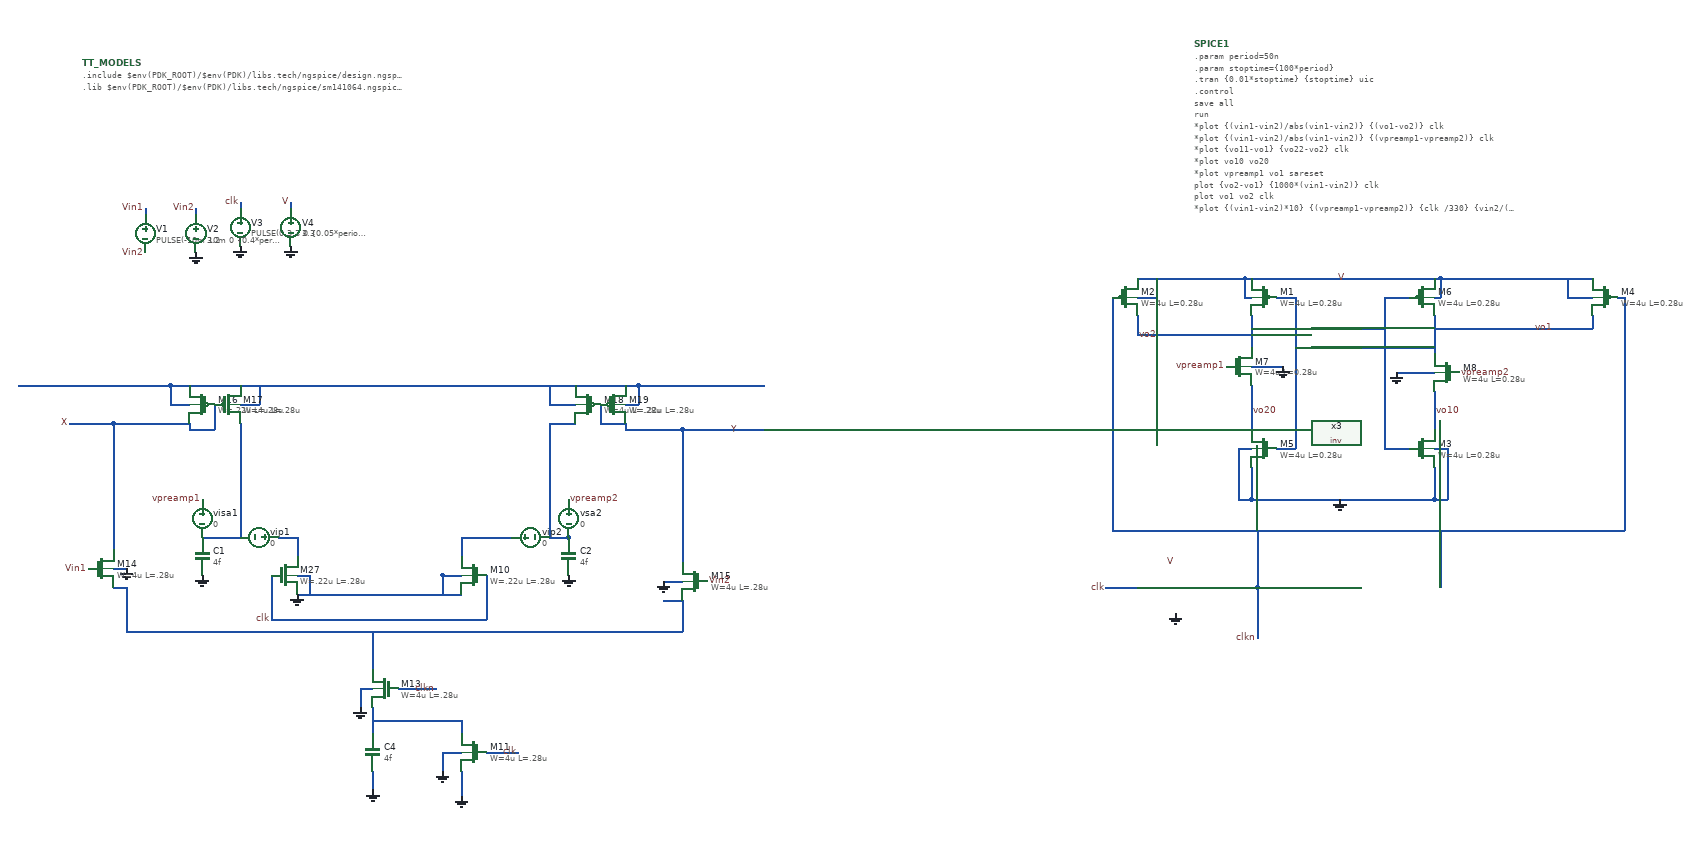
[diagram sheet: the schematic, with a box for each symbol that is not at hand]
v {xschem version=3.4.6RC file_version=1.2
}
G {}
K {}
V {}
S {}
E {}
N 270 -480 270 -470 {
lab=V}
N 190 -480 190 -470 {
lab=clk}
N 1790 -60 1790 -10 {
lab=GND}
N 1850 40 2350 40 {
lab=clkn}
N 2080 -60 2080 -10 {
lab=GND}
N 1770 -90 1790 -90 {
lab=GND}
N 1770 -90 1770 -10 {
lab=GND}
N 2080 -90 2100 -90 {
lab=GND}
N 2100 -90 2100 -10 {
lab=GND}
N 2080 -130 2080 -120 {
lab=vo10}
N 2080 -300 2080 -240 {
lab=vo1}
N 2020 -360 2090 -360 {
lab=V}
N 1790 -130 1790 -120 {
lab=vo20}
N 1790 -300 1790 -250 {
lab=vo2}
N 1780 -330 1790 -330 {
lab=V}
N 1780 -360 1780 -330 {
lab=V}
N 2080 -330 2090 -330 {
lab=V}
N 2090 -360 2090 -330 {
lab=V}
N 1830 -330 1860 -330 {
lab=vo1}
N 1830 -90 1860 -90 {
lab=vo1}
N 1860 -170 1860 -90 {
lab=vo1}
N 1790 -220 1840 -220 {
lab=GND}
N 2000 -130 2000 -90 {
lab=vo2}
N 2000 -90 2040 -90 {
lab=vo2}
N 2020 -210 2080 -210 {
lab=GND}
N 2000 -330 2040 -330 {
lab=vo2}
N 1770 -10 1790 -10 {
lab=GND}
N 1920 -10 2080 -10 {
lab=GND}
N 2080 -10 2100 -10 {
lab=GND}
N 1780 -360 1840 -360 {
lab=V}
N 1940 -360 2020 -360 {
lab=V}
N 1860 -330 1860 -170 {
lab=vo1}
N 2080 -180 2080 -170 {
lab=vo10}
N 1790 -190 1790 -130 {
lab=vo20}
N 2000 -330 2000 -130 {
lab=vo2}
N 2080 -170 2080 -130 {
lab=vo10}
N 1840 -360 1940 -360 {
lab=V}
N 1790 -10 1920 -10 {
lab=GND}
N 1560 130 1610 130 {
lab=clk}
N 2090 40 2090 130 {lab=clkn}
N 120 -470 120 -460 {
lab=Vin2}
N 40 -470 40 -460 {
lab=Vin1}
N 710 50 710 60 {lab=#net1}
N 2090 -360 2330 -360 {lab=V}
N 1610 -360 1780 -360 {lab=V}
N 1610 -330 1640 -330 {lab=V}
N 1640 -360 1640 -330 {lab=V}
N 2290 -330 2330 -330 {lab=V}
N 2290 -360 2290 -330 {lab=V}
N 1610 -300 1610 -270 {lab=vo2}
N 1610 -270 1790 -270 {lab=vo2}
N 2080 -280 2330 -280 {lab=vo1}
N 2330 -300 2330 -280 {lab=vo1}
N 2350 40 2380 40 {lab=clkn}
N 2380 -330 2380 40 {lab=clkn}
N 2370 -330 2380 -330 {lab=clkn}
N 1570 -330 1570 -10 {lab=clkn}
N 1570 -10 1570 40 {lab=clkn}
N 1570 40 1850 40 {lab=clkn}
N 300 110 300 140 {lab=GND}
N 280 140 540 140 {lab=GND}
N 510 110 510 140 {lab=GND}
N 240 110 240 180 {lab=clk}
N 240 180 580 180 {lab=clk}
N 580 110 580 180 {lab=clk}
N 710 50 710 60 {lab=#net1}
N 130 50 130 60 {lab=#net2}
N 130 50 190 50 {lab=#net2}
N 250 50 280 50 {lab=#net3}
N 540 50 620 50 {lab=#net4}
N 680 50 710 50 {lab=#net1}
N 1790 -280 2000 -280 {lab=vo2}
N 1860 -250 2080 -250 {lab=vo1}
N 540 50 540 80 {lab=#net4}
N 280 50 280 80 {lab=#net3}
N 510 110 540 110 {lab=GND}
N 280 110 300 110 {lab=GND}
N 510 110 540 110 {lab=GND}
N 110 -190 800 -190 {lab=#net5}
N 80 -160 110 -160 {lab=#net5}
N 80 -190 80 -160 {lab=#net5}
N 80 -190 110 -190 {lab=#net5}
N 190 -160 220 -160 {lab=#net5}
N 220 -190 220 -160 {lab=#net5}
N 680 -160 720 -160 {lab=#net5}
N 680 -190 680 -160 {lab=#net5}
N 800 -160 820 -160 {lab=#net5}
N 820 -190 820 -160 {lab=#net5}
N 800 -190 820 -190 {lab=#net5}
N 860 120 890 120 {lab=GND}
N 860 150 890 150 {lab=#net6}
N -10 100 10 100 {lab=GND}
N -10 130 10 130 {lab=#net6}
N 150 -160 150 -120 {lab=X}
N 110 -120 150 -120 {lab=X}
N 110 -130 110 -120 {lab=X}
N 0 -130 110 -130 {lab=X}
N 190 -130 190 50 {lab=#net2}
N 680 -130 720 -130 {lab=#net1}
N 680 -130 680 50 {lab=#net1}
N 380 290 400 290 {lab=GND}
N 380 290 380 320 {lab=GND}
N 10 130 10 200 {lab=#net6}
N 10 200 890 200 {lab=#net6}
N 890 150 890 200 {lab=#net6}
N 400 200 400 260 {lab=#net6}
N 760 -130 800 -130 {lab=Y}
N 760 -160 760 -130 {lab=Y}
N 1770 130 1800 130 {lab=clkn}
N 1800 40 1800 130 {lab=clkn}
N 900 -120 1020 -120 {lab=Y}
N -80 -190 80 -190 {lab=#net5}
N 820 -190 1020 -190 {lab=#net5}
N 890 20 890 90 {lab=Y}
N -160 -190 -80 -190 {lab=#net5}
N 510 390 540 390 {lab=GND}
N 510 390 510 420 {lab=GND}
N 400 420 400 450 {lab=GND}
N 400 320 400 360 {lab=#net7}
N 400 340 540 340 {lab=#net7}
N 540 340 540 360 {lab=#net7}
N 540 420 540 460 {lab=GND}
N 890 -120 890 20 {lab=Y}
N 890 -120 900 -120 {lab=Y}
N -10 -130 -10 70 {lab=X}
N -10 -130 -0 -130 {lab=X}
N -80 -130 -10 -130 {lab=X}
N 800 -130 800 -120 {lab=Y}
N 800 -120 890 -120 {lab=Y}
N 580 390 630 390 {lab=clk}
N 1800 130 1800 210 {lab=clkn}
N 440 290 500 290 {lab=clkn}
C {devices/vsource.sym} 190 -440 0 0 {name=V3 value="PULSE(0 3.3 0 \{0.05*period\} \{0.05*period\} \{0.5*period\} \{1*period\})"}
C {devices/gnd.sym} 190 -410 0 0 {name=l4 lab=GND}
C {devices/lab_wire.sym} 190 -480 0 0 {name=p3 sig_type=std_logic lab=clk
}
C {devices/vsource.sym} 270 -440 0 0 {name=V4 value=3.3}
C {devices/gnd.sym} 270 -410 0 0 {name=l5 lab=GND}
C {devices/lab_wire.sym} 270 -480 0 0 {name=p7 sig_type=std_logic lab=V
}
C {devices/code_shown.sym} 1700 -730 0 0 {name=SPICE1 only_toplevel=false value="

.param period=50n
.param stoptime=\{100*period\}
.tran \{0.01*stoptime\} \{stoptime\} uic 
.control
save all
run
*plot \{(vin1-vin2)/abs(vin1-vin2)\} \{(vo1-vo2)\} clk
*plot \{(vin1-vin2)/abs(vin1-vin2)\} \{(vpreamp1-vpreamp2)\} clk
*plot \{vo11-vo1\} \{vo22-vo2\} clk
*plot vo10 vo20
*plot vpreamp1 vo1 sareset
plot \{vo2-vo1\} \{1000*(vin1-vin2)\} clk
plot vo1 vo2 clk
*plot \{(vin1-vin2)*10\} \{(vpreamp1-vpreamp2)\} \{clk /330\} \{vin2/(100)\}
plot \{(vin1-vin2)*1000\} vpreamp1 vpreamp2 \{clk\} \{vin2\}
plot \{(vpreamp1-vpreamp2)\} \{(vin1-vin2)\} \{clk/330\}
plot X Y clk
plot \{(X-Y)\} \{clk/3000\}
plot vpreamp1
*plot clk sareset
*plot i(vip1) i(vip2) i(visa1) i(vsa2) clk/3300
.endc"}
C {devices/code.sym} -60 -700 0 0 {name=TT_MODELS 
only_toplevel=true 
format="tcleval(  @value  )"
value="
.include $env(PDK_ROOT)/$env(PDK)/libs.tech/ngspice/design.ngspice
.lib $env(PDK_ROOT)/$env(PDK)/libs.tech/ngspice/sm141064.ngspice typical
"
spice_ignore=false}
C {symbols/pfet_03v3.sym} 1810 -330 0 1 {name=M1
L=0.28u
W=4u
nf=1
m=1
ad="'int((nf+1)/2) * W/nf * 0.18u'"
pd="'2*int((nf+1)/2) * (W/nf + 0.18u)'"
as="'int((nf+2)/2) * W/nf * 0.18u'"
ps="'2*int((nf+2)/2) * (W/nf + 0.18u)'"
nrd="'0.18u / W'" nrs="'0.18u / W'"
sa=0 sb=0 sd=0
model=pfet_03v3
spiceprefix=X
}
C {symbols/pfet_03v3.sym} 1590 -330 0 0 {name=M2
L=0.28u
W=4u
nf=1
m=1
ad="'int((nf+1)/2) * W/nf * 0.18u'"
pd="'2*int((nf+1)/2) * (W/nf + 0.18u)'"
as="'int((nf+2)/2) * W/nf * 0.18u'"
ps="'2*int((nf+2)/2) * (W/nf + 0.18u)'"
nrd="'0.18u / W'" nrs="'0.18u / W'"
sa=0 sb=0 sd=0
model=pfet_03v3
spiceprefix=X
}
C {symbols/nfet_03v3.sym} 2060 -90 0 0 {name=M3
L=0.28u
W=4u
nf=1
m=1
ad="'int((nf+1)/2) * W/nf * 0.18u'"
pd="'2*int((nf+1)/2) * (W/nf + 0.18u)'"
as="'int((nf+2)/2) * W/nf * 0.18u'"
ps="'2*int((nf+2)/2) * (W/nf + 0.18u)'"
nrd="'0.18u / W'" nrs="'0.18u / W'"
sa=0 sb=0 sd=0
model=nfet_03v3
spiceprefix=X
}
C {symbols/pfet_03v3.sym} 2350 -330 0 1 {name=M4
L=0.28u
W=4u
nf=1
m=1
ad="'int((nf+1)/2) * W/nf * 0.18u'"
pd="'2*int((nf+1)/2) * (W/nf + 0.18u)'"
as="'int((nf+2)/2) * W/nf * 0.18u'"
ps="'2*int((nf+2)/2) * (W/nf + 0.18u)'"
nrd="'0.18u / W'" nrs="'0.18u / W'"
sa=0 sb=0 sd=0
model=pfet_03v3
spiceprefix=X
}
C {symbols/nfet_03v3.sym} 1810 -90 0 1 {name=M5
L=0.28u
W=4u
nf=1
m=1
ad="'int((nf+1)/2) * W/nf * 0.18u'"
pd="'2*int((nf+1)/2) * (W/nf + 0.18u)'"
as="'int((nf+2)/2) * W/nf * 0.18u'"
ps="'2*int((nf+2)/2) * (W/nf + 0.18u)'"
nrd="'0.18u / W'" nrs="'0.18u / W'"
sa=0 sb=0 sd=0
model=nfet_03v3
spiceprefix=X
}
C {symbols/pfet_03v3.sym} 2060 -330 0 0 {name=M6
L=0.28u
W=4u
nf=1
m=1
ad="'int((nf+1)/2) * W/nf * 0.18u'"
pd="'2*int((nf+1)/2) * (W/nf + 0.18u)'"
as="'int((nf+2)/2) * W/nf * 0.18u'"
ps="'2*int((nf+2)/2) * (W/nf + 0.18u)'"
nrd="'0.18u / W'" nrs="'0.18u / W'"
sa=0 sb=0 sd=0
model=pfet_03v3
spiceprefix=X
}
C {symbols/nfet_03v3.sym} 1770 -220 0 0 {name=M7
L=0.28u
W=4u
nf=1
m=1
ad="'int((nf+1)/2) * W/nf * 0.18u'"
pd="'2*int((nf+1)/2) * (W/nf + 0.18u)'"
as="'int((nf+2)/2) * W/nf * 0.18u'"
ps="'2*int((nf+2)/2) * (W/nf + 0.18u)'"
nrd="'0.18u / W'" nrs="'0.18u / W'"
sa=0 sb=0 sd=0
model=nfet_03v3
spiceprefix=X
}
C {symbols/nfet_03v3.sym} 2100 -210 0 1 {name=M8
L=0.28u
W=4u
nf=1
m=1
ad="'int((nf+1)/2) * W/nf * 0.18u'"
pd="'2*int((nf+1)/2) * (W/nf + 0.18u)'"
as="'int((nf+2)/2) * W/nf * 0.18u'"
ps="'2*int((nf+2)/2) * (W/nf + 0.18u)'"
nrd="'0.18u / W'" nrs="'0.18u / W'"
sa=0 sb=0 sd=0
model=nfet_03v3
spiceprefix=X
}
C {inv.sym} 1670 130 0 0 {name=x3 cl=0.28u wp=0.44u wn=0.22u wx=4u}
C {symbols/nfet_03v3.sym} 260 110 0 0 {name=M27
L=.28u
W=.22u
nf=1
m=1
ad="'int((nf+1)/2) * W/nf * 0.18u'"
pd="'2*int((nf+1)/2) * (W/nf + 0.18u)'"
as="'int((nf+2)/2) * W/nf * 0.18u'"
ps="'2*int((nf+2)/2) * (W/nf + 0.18u)'"
nrd="'0.18u / W'" nrs="'0.18u / W'"
sa=0 sb=0 sd=0
model=nfet_03v3
spiceprefix=X
}
C {devices/lab_wire.sym} 1940 -360 0 0 {name=p4 lab=V
W=3u}
C {devices/gnd.sym} 1670 170 0 0 {name=l1 lab=GND}
C {devices/gnd.sym} 280 140 0 0 {name=l2 lab=GND}
C {devices/lab_wire.sym} 240 180 0 0 {name=p8 sig_type=std_logic lab=clk
}
C {devices/lab_wire.sym} 1560 130 0 0 {name=p9 sig_type=std_logic lab=clk
}
C {devices/lab_wire.sym} 130 -10 0 0 {name=p10 sig_type=std_logic lab=vpreamp1}
C {devices/lab_wire.sym} 1750 -220 0 0 {name=p12 sig_type=std_logic lab=vpreamp1}
C {devices/lab_wire.sym} 2120 -210 0 1 {name=p14 sig_type=std_logic lab=vpreamp2
}
C {devices/lab_wire.sym} 1670 90 0 0 {name=p16 lab=V
W=3u}
C {devices/lab_wire.sym} 2270 -280 0 0 {name=p15 sig_type=std_logic lab=vo1
}
C {devices/lab_wire.sym} 1610 -270 0 1 {name=p17 sig_type=std_logic lab=vo2}
C {devices/vsource.sym} 40 -430 0 0 {name=V1 value="PULSE(-10m 10m 0 \{0.4*period\} \{0.4*period\} \{4*period\} \{8*period\})"}
C {devices/vsource.sym} 120 -430 0 0 {name=V2 value=3.2}
C {devices/gnd.sym} 120 -400 0 0 {name=l3 lab=GND}
C {devices/lab_wire.sym} 40 -470 0 0 {name=p1 sig_type=std_logic lab=Vin1}
C {devices/lab_wire.sym} 120 -470 0 0 {name=p2 sig_type=std_logic lab=Vin2}
C {devices/lab_wire.sym} 40 -400 0 0 {name=p13 sig_type=std_logic lab=Vin2}
C {devices/vsource.sym} 220 50 1 0 {name=vip1 value=0}
C {devices/vsource.sym} 130 20 0 0 {name=visa1 value=0}
C {devices/vsource.sym} 650 50 3 0 {name=vip2 value=0}
C {devices/vsource.sym} 710 20 0 0 {name=vsa2 value=0}
C {devices/lab_wire.sym} 710 -10 0 1 {name=p23 sig_type=std_logic lab=vpreamp2
}
C {devices/gnd.sym} 1930 -10 0 0 {name=l6 lab=GND}
C {symbols/nfet_03v3.sym} 560 110 0 1 {name=M10
L=.28u
W=.22u
nf=1
m=1
ad="'int((nf+1)/2) * W/nf * 0.18u'"
pd="'2*int((nf+1)/2) * (W/nf + 0.18u)'"
as="'int((nf+2)/2) * W/nf * 0.18u'"
ps="'2*int((nf+2)/2) * (W/nf + 0.18u)'"
nrd="'0.18u / W'" nrs="'0.18u / W'"
sa=0 sb=0 sd=0
model=nfet_03v3
spiceprefix=X
}
C {devices/gnd.sym} 10 100 0 0 {name=l7 lab=GND}
C {devices/gnd.sym} 860 120 0 0 {name=l8 lab=GND}
C {devices/gnd.sym} 2020 -210 0 0 {name=l9 lab=GND}
C {devices/gnd.sym} 1840 -220 0 0 {name=l10 lab=GND}
C {devices/lab_wire.sym} 1790 -150 0 1 {name=p19 sig_type=std_logic lab=vo20}
C {devices/lab_wire.sym} 2080 -150 0 1 {name=p20 sig_type=std_logic lab=vo10}
C {symbols/nfet_03v3.sym} 420 290 0 1 {name=M13
L=.28u
W=4u
nf=1
m=1
ad="'int((nf+1)/2) * W/nf * 0.18u'"
pd="'2*int((nf+1)/2) * (W/nf + 0.18u)'"
as="'int((nf+2)/2) * W/nf * 0.18u'"
ps="'2*int((nf+2)/2) * (W/nf + 0.18u)'"
nrd="'0.18u / W'" nrs="'0.18u / W'"
sa=0 sb=0 sd=0
model=nfet_03v3
spiceprefix=X
}
C {symbols/nfet_03v3.sym} -30 100 0 0 {name=M14
L=.28u
W=4u
nf=1
m=1
ad="'int((nf+1)/2) * W/nf * 0.18u'"
pd="'2*int((nf+1)/2) * (W/nf + 0.18u)'"
as="'int((nf+2)/2) * W/nf * 0.18u'"
ps="'2*int((nf+2)/2) * (W/nf + 0.18u)'"
nrd="'0.18u / W'" nrs="'0.18u / W'"
sa=0 sb=0 sd=0
model=nfet_03v3
spiceprefix=X
}
C {symbols/nfet_03v3.sym} 910 120 0 1 {name=M15
L=.28u
W=4u
nf=1
m=1
ad="'int((nf+1)/2) * W/nf * 0.18u'"
pd="'2*int((nf+1)/2) * (W/nf + 0.18u)'"
as="'int((nf+2)/2) * W/nf * 0.18u'"
ps="'2*int((nf+2)/2) * (W/nf + 0.18u)'"
nrd="'0.18u / W'" nrs="'0.18u / W'"
sa=0 sb=0 sd=0
model=nfet_03v3
spiceprefix=X
}
C {symbols/pfet_03v3.sym} 130 -160 0 1 {name=M16
L=.28u
W=.22u
nf=1
m=1
ad="'int((nf+1)/2) * W/nf * 0.18u'"
pd="'2*int((nf+1)/2) * (W/nf + 0.18u)'"
as="'int((nf+2)/2) * W/nf * 0.18u'"
ps="'2*int((nf+2)/2) * (W/nf + 0.18u)'"
nrd="'0.18u / W'" nrs="'0.18u / W'"
sa=0 sb=0 sd=0
model=pfet_03v3
spiceprefix=X
}
C {symbols/pfet_03v3.sym} 170 -160 0 0 {name=M17
L=.28u
W=4u
nf=1
m=1
ad="'int((nf+1)/2) * W/nf * 0.18u'"
pd="'2*int((nf+1)/2) * (W/nf + 0.18u)'"
as="'int((nf+2)/2) * W/nf * 0.18u'"
ps="'2*int((nf+2)/2) * (W/nf + 0.18u)'"
nrd="'0.18u / W'" nrs="'0.18u / W'"
sa=0 sb=0 sd=0
model=pfet_03v3
spiceprefix=X
}
C {symbols/pfet_03v3.sym} 740 -160 0 1 {name=M18
L=.28u
W=4u
nf=1
m=1
ad="'int((nf+1)/2) * W/nf * 0.18u'"
pd="'2*int((nf+1)/2) * (W/nf + 0.18u)'"
as="'int((nf+2)/2) * W/nf * 0.18u'"
ps="'2*int((nf+2)/2) * (W/nf + 0.18u)'"
nrd="'0.18u / W'" nrs="'0.18u / W'"
sa=0 sb=0 sd=0
model=pfet_03v3
spiceprefix=X
}
C {symbols/pfet_03v3.sym} 780 -160 0 0 {name=M19
L=.28u
W=.22u
nf=1
m=1
ad="'int((nf+1)/2) * W/nf * 0.18u'"
pd="'2*int((nf+1)/2) * (W/nf + 0.18u)'"
as="'int((nf+2)/2) * W/nf * 0.18u'"
ps="'2*int((nf+2)/2) * (W/nf + 0.18u)'"
nrd="'0.18u / W'" nrs="'0.18u / W'"
sa=0 sb=0 sd=0
model=pfet_03v3
spiceprefix=X
}
C {devices/gnd.sym} 400 450 0 0 {name=l11 lab=GND}
C {devices/lab_wire.sym} -50 100 0 0 {name=p22 sig_type=std_logic lab=Vin1}
C {devices/lab_wire.sym} 930 120 0 1 {name=p24 sig_type=std_logic lab=Vin2}
C {devices/lab_wire.sym} 1800 210 0 0 {name=p18 sig_type=std_logic lab=clkn
}
C {devices/lab_wire.sym} -80 -130 0 0 {name=p25 sig_type=std_logic lab=X}
C {devices/lab_wire.sym} 980 -120 0 0 {name=p26 sig_type=std_logic lab=Y}
C {devices/capa.sym} 130 80 0 0 {name=C1
m=1
value=4f
footprint=1206
device="ceramic capacitor"}
C {devices/capa.sym} 710 80 0 0 {name=C2
m=1
value=4f
footprint=1206
device="ceramic capacitor"}
C {devices/gnd.sym} 710 110 0 0 {name=l12 lab=GND}
C {devices/gnd.sym} 130 110 0 0 {name=l13 lab=GND}
C {devices/capa.sym} 400 390 0 0 {name=C4
m=1
value=4f
footprint=1206
device="ceramic capacitor"}
C {devices/gnd.sym} 380 320 0 0 {name=l14 lab=GND}
C {symbols/nfet_03v3.sym} 560 390 0 1 {name=M11
L=.28u
W=4u
nf=1
m=1
ad="'int((nf+1)/2) * W/nf * 0.18u'"
pd="'2*int((nf+1)/2) * (W/nf + 0.18u)'"
as="'int((nf+2)/2) * W/nf * 0.18u'"
ps="'2*int((nf+2)/2) * (W/nf + 0.18u)'"
nrd="'0.18u / W'" nrs="'0.18u / W'"
sa=0 sb=0 sd=0
model=nfet_03v3
spiceprefix=X
}
C {devices/gnd.sym} 510 420 0 0 {name=l15 lab=GND}
C {devices/gnd.sym} 540 460 0 0 {name=l16 lab=GND}
C {devices/lab_wire.sym} 630 390 0 0 {name=p5 sig_type=std_logic lab=clk
}
C {devices/lab_wire.sym} 500 290 0 0 {name=p6 sig_type=std_logic lab=clkn
}
